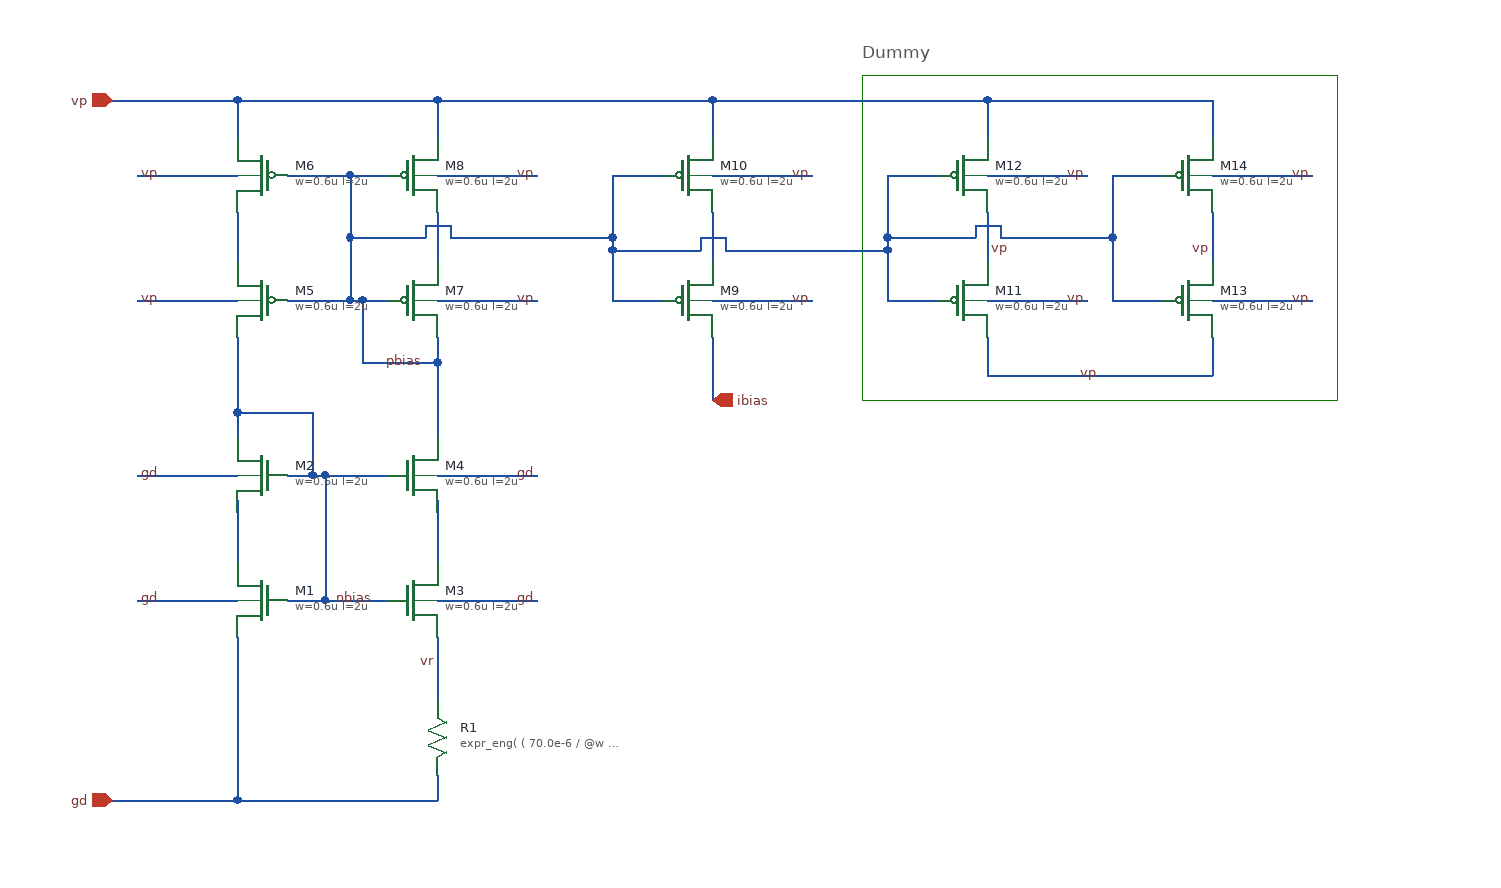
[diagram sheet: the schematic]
v {xschem version=3.4.8RC file_version=1.3}
G {}
K {}
V {}
S {}
F {}
E {}
L 4 600 -580 600 -320 {}
L 4 600 -320 980 -320 {}
L 4 980 -580 980 -320 {}
L 4 600 -580 980 -580 {}
T {Dummy} 600 -610 0 0 0.4 0.4 {}
N 260 -20 260 0 {lab=gd}
N 260 -130 260 -80 {lab=vr}
N 100 -130 100 0 {lab=gd}
N 170 -160 220 -160 {lab=nbias}
N 100 -560 260 -560 {lab=vp}
N 20 -400 100 -400 {lab=vp}
N 260 -400 340 -400 {lab=vp}
N 260 -160 340 -160 {lab=gd}
N 20 -160 100 -160 {lab=gd}
N 140 -160 170 -160 {lab=nbias}
N 200 -400 200 -350 {lab=pbias}
N 200 -400 220 -400 {lab=pbias}
N 260 -370 260 -350 {lab=pbias}
N 260 -260 340 -260 {lab=gd}
N 20 -260 100 -260 {lab=gd}
N 160 -260 170 -260 {lab=nbias}
N 170 -260 170 -160 {lab=nbias}
N 170 -260 220 -260 {lab=nbias}
N 160 -310 160 -260 {lab=nbias}
N 140 -260 160 -260 {lab=nbias}
N 100 -310 160 -310 {lab=nbias}
N 100 -310 100 -290 {lab=nbias}
N 20 -500 100 -500 {lab=vp}
N 260 -500 340 -500 {lab=vp}
N 100 -240 100 -190 {lab=#net1}
N 260 -240 260 -190 {lab=#net2}
N 100 -370 100 -310 {lab=nbias}
N 260 -350 260 -290 {lab=pbias}
N 260 -470 260 -420 {lab=#net3}
N 100 -470 100 -420 {lab=#net4}
N 100 -560 100 -530 {lab=vp}
N 260 -560 260 -530 {lab=vp}
N 200 -350 260 -350 {lab=pbias}
N 190 -400 200 -400 {lab=pbias}
N 190 -450 190 -400 {lab=pbias}
N 190 -500 220 -500 {lab=pbias}
N 140 -500 190 -500 {lab=pbias}
N 140 -400 190 -400 {lab=pbias}
N 480 -400 560 -400 {lab=vp}
N 480 -500 560 -500 {lab=vp}
N 400 -400 440 -400 {lab=pbias}
N 400 -440 400 -400 {lab=pbias}
N 400 -500 440 -500 {lab=pbias}
N 480 -470 480 -430 {lab=#net5}
N 480 -560 480 -530 {lab=vp}
N 190 -450 250 -450 {lab=pbias}
N 190 -500 190 -450 {lab=pbias}
N 250 -460 250 -450 {lab=pbias}
N 250 -460 270 -460 {lab=pbias}
N 270 -460 270 -450 {lab=pbias}
N 270 -450 400 -450 {lab=pbias}
N 400 -500 400 -450 {lab=pbias}
N 260 -560 480 -560 {lab=vp}
N 480 -370 480 -320 {lab=ibias}
N 0 -560 100 -560 {lab=vp}
N 100 0 260 -0 {lab=gd}
N -0 0 100 0 {lab=gd}
N 700 -400 780 -400 {lab=vp}
N 700 -500 780 -500 {lab=vp}
N 700 -470 700 -430 {lab=vp}
N 880 -400 960 -400 {lab=vp}
N 880 -500 960 -500 {lab=vp}
N 880 -470 880 -430 {lab=vp}
N 620 -400 660 -400 {lab=pbias}
N 620 -500 660 -500 {lab=pbias}
N 620 -440 620 -400 {lab=pbias}
N 800 -400 840 -400 {lab=pbias}
N 800 -500 840 -500 {lab=pbias}
N 800 -450 800 -400 {lab=pbias}
N 400 -440 470 -440 {lab=pbias}
N 400 -450 400 -440 {lab=pbias}
N 470 -450 470 -440 {lab=pbias}
N 470 -450 490 -450 {lab=pbias}
N 490 -450 490 -440 {lab=pbias}
N 490 -440 620 -440 {lab=pbias}
N 620 -450 620 -440 {lab=pbias}
N 620 -450 690 -450 {lab=pbias}
N 620 -500 620 -450 {lab=pbias}
N 690 -460 690 -450 {lab=pbias}
N 690 -460 710 -460 {lab=pbias}
N 710 -460 710 -450 {lab=pbias}
N 710 -450 800 -450 {lab=pbias}
N 800 -500 800 -450 {lab=pbias}
N 480 -560 700 -560 {lab=vp}
N 700 -560 700 -530 {lab=vp}
N 700 -560 880 -560 {lab=vp}
N 880 -560 880 -530 {lab=vp}
N 700 -370 700 -340 {lab=vp}
N 700 -340 880 -340 {lab=vp}
N 880 -370 880 -340 {lab=vp}
C {lab_wire.sym} 260 -110 3 0 {name=p22 sig_type=std_logic lab=vr}
C {lab_wire.sym} 20 -400 0 1 {name=p13 sig_type=std_logic lab=vp}
C {lab_wire.sym} 340 -400 0 0 {name=p14 sig_type=std_logic lab=vp}
C {lab_wire.sym} 340 -160 0 0 {name=p15 sig_type=std_logic lab=gd}
C {lab_wire.sym} 20 -160 0 1 {name=p16 sig_type=std_logic lab=gd}
C {lab_wire.sym} 210 -160 2 1 {name=p19 sig_type=std_logic lab=nbias}
C {lab_wire.sym} 250 -350 2 1 {name=p20 sig_type=std_logic lab=pbias}
C {sg13cmos5l_pr/sg13_hv_nmos.sym} 120 -160 0 1 {name=M1
l=2u
w=0.6u
ng=1
m=1
model=sg13_hv_nmos
spiceprefix=X
}
C {sg13cmos5l_pr/sg13_hv_nmos.sym} 240 -160 0 0 {name=M3
l=2u
w=0.6u
ng=1
m=4
model=sg13_hv_nmos
spiceprefix=X
}
C {sg13cmos5l_pr/sg13_hv_pmos.sym} 240 -400 0 0 {name=M7
l=2u
w=0.6u
ng=1
m=1
model=sg13_hv_pmos
spiceprefix=X
}
C {sg13cmos5l_pr/sg13_hv_pmos.sym} 120 -400 0 1 {name=M5
l=2u
w=0.6u
ng=1
m=1
model=sg13_hv_pmos
spiceprefix=X
}
C {lab_wire.sym} 340 -260 0 0 {name=p33 sig_type=std_logic lab=gd}
C {lab_wire.sym} 20 -260 0 1 {name=p34 sig_type=std_logic lab=gd}
C {sg13cmos5l_pr/sg13_hv_nmos.sym} 120 -260 0 1 {name=M2
l=2u
w=0.6u
ng=1
m=1
model=sg13_hv_nmos
spiceprefix=X
}
C {sg13cmos5l_pr/sg13_hv_nmos.sym} 240 -260 0 0 {name=M4
l=2u
w=0.6u
ng=1
m=4
model=sg13_hv_nmos
spiceprefix=X
}
C {lab_wire.sym} 20 -500 0 1 {name=p35 sig_type=std_logic lab=vp}
C {lab_wire.sym} 340 -500 0 0 {name=p36 sig_type=std_logic lab=vp}
C {sg13cmos5l_pr/sg13_hv_pmos.sym} 240 -500 0 0 {name=M8
l=2u
w=0.6u
ng=1
m=1
model=sg13_hv_pmos
spiceprefix=X
}
C {sg13cmos5l_pr/sg13_hv_pmos.sym} 120 -500 0 1 {name=M6
l=2u
w=0.6u
ng=1
m=1
model=sg13_hv_pmos
spiceprefix=X
}
C {lab_wire.sym} 560 -400 0 0 {name=p23 sig_type=std_logic lab=vp}
C {sg13cmos5l_pr/sg13_hv_pmos.sym} 460 -400 0 0 {name=M9
l=2u
w=0.6u
ng=1
m=1
model=sg13_hv_pmos
spiceprefix=X
}
C {lab_wire.sym} 560 -500 0 0 {name=p24 sig_type=std_logic lab=vp}
C {sg13cmos5l_pr/sg13_hv_pmos.sym} 460 -500 0 0 {name=M10
l=2u
w=0.6u
ng=1
m=1
model=sg13_hv_pmos
spiceprefix=X
}
C {ipin.sym} 0 -560 0 0 {name=p1 lab=vp}
C {ipin.sym} 0 0 0 0 {name=p2 lab=gd}
C {opin.sym} 480 -320 1 0 {name=p3 lab=ibias}
C {sg13cmos5l_pr/rppd.sym} 260 -50 0 0 {name=R1
w=0.5e-6
l=2e-6
model=rppd
body=sub!
spiceprefix=X
b=20
m=1
value="expr_eng(  ( 70.0e-6 / @w + 260.0 * ( (@b + 1)* @l + ( 1.081*( @w + 6.0e-9 ) + 0.18e-6 )*@b ) / ( @w + 6.0e-9 ) ) / @m  )"
}
C {lab_wire.sym} 780 -400 0 0 {name=p4 sig_type=std_logic lab=vp}
C {sg13cmos5l_pr/sg13_hv_pmos.sym} 680 -400 0 0 {name=M11
l=2u
w=0.6u
ng=1
m=1
model=sg13_hv_pmos
spiceprefix=X
}
C {lab_wire.sym} 780 -500 0 0 {name=p5 sig_type=std_logic lab=vp}
C {sg13cmos5l_pr/sg13_hv_pmos.sym} 680 -500 0 0 {name=M12
l=2u
w=0.6u
ng=1
m=1
model=sg13_hv_pmos
spiceprefix=X
}
C {lab_wire.sym} 960 -400 0 0 {name=p6 sig_type=std_logic lab=vp}
C {sg13cmos5l_pr/sg13_hv_pmos.sym} 860 -400 0 0 {name=M13
l=2u
w=0.6u
ng=1
m=1
model=sg13_hv_pmos
spiceprefix=X
}
C {lab_wire.sym} 960 -500 0 0 {name=p7 sig_type=std_logic lab=vp}
C {sg13cmos5l_pr/sg13_hv_pmos.sym} 860 -500 0 0 {name=M14
l=2u
w=0.6u
ng=1
m=1
model=sg13_hv_pmos
spiceprefix=X
}
C {lab_wire.sym} 790 -340 0 0 {name=p8 sig_type=std_logic lab=vp}
C {lab_wire.sym} 880 -440 0 0 {name=p9 sig_type=std_logic lab=vp}
C {lab_wire.sym} 700 -440 0 1 {name=p10 sig_type=std_logic lab=vp}
